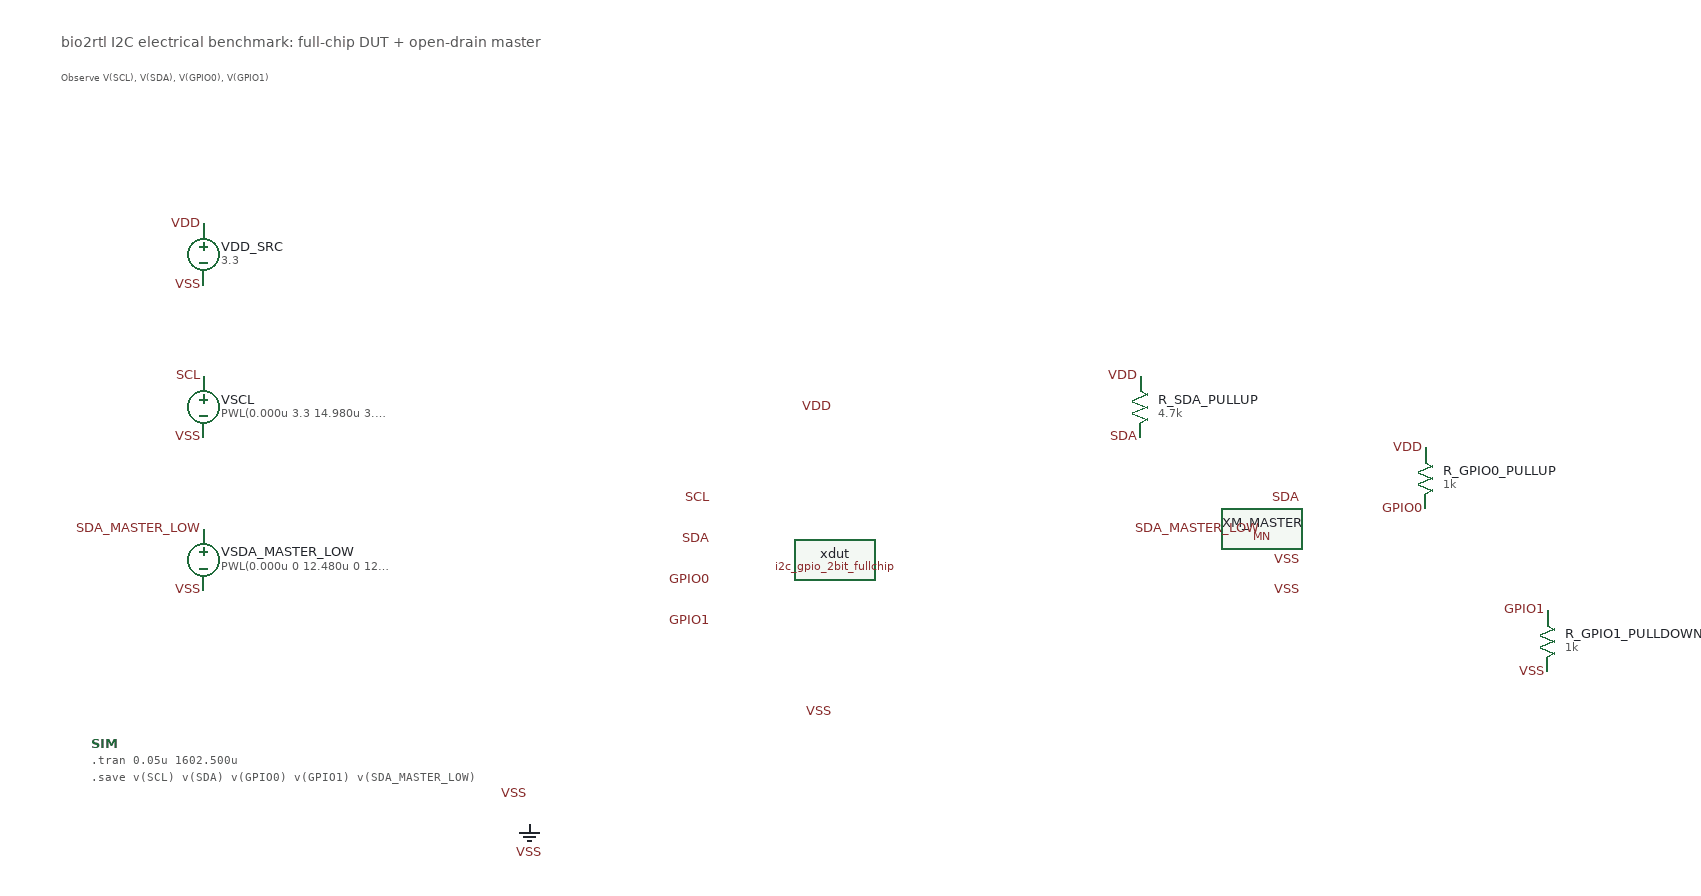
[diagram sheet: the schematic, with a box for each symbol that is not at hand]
v {xschem version=3.4.8RC file_version=1.3}
G {}
K {}
V {}
S {}
F {}
E {}
T {bio2rtl I2C electrical benchmark: full-chip DUT + open-drain master} -760 -520 0 0 0.42 0.42 {}
T {Observe V(SCL), V(SDA), V(GPIO0), V(GPIO1)} -760 -485 0 0 0.28 0.28 {}
C {i2c_gpio_2bit_fullchip.sym} 0 0 0 0 {name=xdut}
C {devices/lab_pin.sym} -120 -60 0 0 {name=d1 sig_type=std_logic lab=SCL}
C {devices/lab_pin.sym} -120 -20 0 0 {name=d2 sig_type=std_logic lab=SDA}
C {devices/lab_pin.sym} -120 20 0 0 {name=d3 sig_type=std_logic lab=GPIO0}
C {devices/lab_pin.sym} -120 60 0 0 {name=d4 sig_type=std_logic lab=GPIO1}
C {devices/lab_pin.sym} 0 -150 0 0 {name=d5 sig_type=std_logic lab=VDD}
C {devices/lab_pin.sym} 0 150 0 0 {name=d6 sig_type=std_logic lab=VSS}
C {devices/vsource.sym} -620 -300 0 0 {name=VDD_SRC value=3.3 savecurrent=false}
C {devices/lab_pin.sym} -620 -330 1 0 {name=vddp sig_type=std_logic lab=VDD}
C {devices/lab_pin.sym} -620 -270 1 0 {name=vddn sig_type=std_logic lab=VSS}
C {devices/vsource.sym} -620 -150 0 0 {name=VSCL value="PWL(0.000u 3.3 14.980u 3.3 15.000u 0 22.480u 0 22.500u 3.3 27.480u 3.3 27.500u 0 32.480u 0 32.500u 3.3 37.480u 3.3 37.500u 0 42.480u 0 42.500u 3.3 47.480u 3.3 47.500u 0 52.480u 0 52.500u 3.3 57.480u 3.3 57.500u 0 62.480u 0 62.500u 3.3 67.480u 3.3 67.500u 0 72.480u 0 72.500u 3.3 77.480u 3.3 77.500u 0 82.480u 0 82.500u 3.3 87.480u 3.3 87.500u 0 92.480u 0 92.500u 3.3 97.480u 3.3 97.500u 0 102.480u 0 102.500u 3.3 107.480u 3.3 107.500u 0 112.480u 0 112.500u 3.3 117.480u 3.3 117.500u 0 122.480u 0 122.500u 3.3 127.480u 3.3 127.500u 0 132.480u 0 132.500u 3.3 137.480u 3.3 137.500u 0 142.480u 0 142.500u 3.3 147.480u 3.3 147.500u 0 152.480u 0 152.500u 3.3 157.480u 3.3 157.500u 0 162.480u 0 162.500u 3.3 167.480u 3.3 167.500u 0 172.480u 0 172.500u 3.3 177.480u 3.3 177.500u 0 182.480u 0 182.500u 3.3 187.480u 3.3 187.500u 0 192.480u 0 192.500u 3.3 197.480u 3.3 197.500u 0 202.480u 0 202.500u 3.3 207.480u 3.3 207.500u 0 212.480u 0 212.500u 3.3 217.480u 3.3 217.500u 0 222.480u 0 222.500u 3.3 227.480u 3.3 227.500u 0 232.480u 0 232.500u 3.3 237.480u 3.3 237.500u 0 242.480u 0 242.500u 3.3 247.480u 3.3 247.500u 0 252.480u 0 252.500u 3.3 257.480u 3.3 257.500u 0 262.480u 0 262.500u 3.3 267.480u 3.3 267.500u 0 272.480u 0 272.500u 3.3 277.480u 3.3 277.500u 0 282.480u 0 282.500u 3.3 287.480u 3.3 287.500u 0 294.980u 0 295.000u 3.3 324.980u 3.3 325.000u 0 332.480u 0 332.500u 3.3 337.480u 3.3 337.500u 0 342.480u 0 342.500u 3.3 347.480u 3.3 347.500u 0 352.480u 0 352.500u 3.3 357.480u 3.3 357.500u 0 362.480u 0 362.500u 3.3 367.480u 3.3 367.500u 0 372.480u 0 372.500u 3.3 377.480u 3.3 377.500u 0 382.480u 0 382.500u 3.3 387.480u 3.3 387.500u 0 392.480u 0 392.500u 3.3 397.480u 3.3 397.500u 0 402.480u 0 402.500u 3.3 407.480u 3.3 407.500u 0 412.480u 0 412.500u 3.3 417.480u 3.3 417.500u 0 422.480u 0 422.500u 3.3 427.480u 3.3 427.500u 0 432.480u 0 432.500u 3.3 437.480u 3.3 437.500u 0 442.480u 0 442.500u 3.3 447.480u 3.3 447.500u 0 452.480u 0 452.500u 3.3 457.480u 3.3 457.500u 0 462.480u 0 462.500u 3.3 467.480u 3.3 467.500u 0 472.480u 0 472.500u 3.3 477.480u 3.3 477.500u 0 482.480u 0 482.500u 3.3 487.480u 3.3 487.500u 0 492.480u 0 492.500u 3.3 497.480u 3.3 497.500u 0 502.480u 0 502.500u 3.3 507.480u 3.3 507.500u 0 512.480u 0 512.500u 3.3 517.480u 3.3 517.500u 0 522.480u 0 522.500u 3.3 527.480u 3.3 527.500u 0 532.480u 0 532.500u 3.3 537.480u 3.3 537.500u 0 542.480u 0 542.500u 3.3 547.480u 3.3 547.500u 0 552.480u 0 552.500u 3.3 557.480u 3.3 557.500u 0 562.480u 0 562.500u 3.3 567.480u 3.3 567.500u 0 572.480u 0 572.500u 3.3 577.480u 3.3 577.500u 0 582.480u 0 582.500u 3.3 587.480u 3.3 587.500u 0 592.480u 0 592.500u 3.3 597.480u 3.3 597.500u 0 604.980u 0 605.000u 3.3 634.980u 3.3 635.000u 0 642.480u 0 642.500u 3.3 647.480u 3.3 647.500u 0 652.480u 0 652.500u 3.3 657.480u 3.3 657.500u 0 662.480u 0 662.500u 3.3 667.480u 3.3 667.500u 0 672.480u 0 672.500u 3.3 677.480u 3.3 677.500u 0 682.480u 0 682.500u 3.3 687.480u 3.3 687.500u 0 692.480u 0 692.500u 3.3 697.480u 3.3 697.500u 0 702.480u 0 702.500u 3.3 707.480u 3.3 707.500u 0 712.480u 0 712.500u 3.3 717.480u 3.3 717.500u 0 722.480u 0 722.500u 3.3 727.480u 3.3 727.500u 0 732.480u 0 732.500u 3.3 737.480u 3.3 737.500u 0 742.480u 0 742.500u 3.3 747.480u 3.3 747.500u 0 752.480u 0 752.500u 3.3 757.480u 3.3 757.500u 0 762.480u 0 762.500u 3.3 767.480u 3.3 767.500u 0 772.480u 0 772.500u 3.3 777.480u 3.3 777.500u 0 782.480u 0 782.500u 3.3 787.480u 3.3 787.500u 0 792.480u 0 792.500u 3.3 797.480u 3.3 797.500u 0 802.480u 0 802.500u 3.3 807.480u 3.3 807.500u 0 812.480u 0 812.500u 3.3 817.480u 3.3 817.500u 0 822.480u 0 822.500u 3.3 827.480u 3.3 827.500u 0 832.480u 0 832.500u 3.3 837.480u 3.3 837.500u 0 842.480u 0 842.500u 3.3 847.480u 3.3 847.500u 0 852.480u 0 852.500u 3.3 857.480u 3.3 857.500u 0 862.480u 0 862.500u 3.3 867.480u 3.3 867.500u 0 872.480u 0 872.500u 3.3 877.480u 3.3 877.500u 0 882.480u 0 882.500u 3.3 887.480u 3.3 887.500u 0 892.480u 0 892.500u 3.3 897.480u 3.3 897.500u 0 902.480u 0 902.500u 3.3 907.480u 3.3 907.500u 0 914.980u 0 915.000u 3.3 944.980u 3.3 945.000u 0 952.480u 0 952.500u 3.3 957.480u 3.3 957.500u 0 962.480u 0 962.500u 3.3 967.480u 3.3 967.500u 0 972.480u 0 972.500u 3.3 977.480u 3.3 977.500u 0 982.480u 0 982.500u 3.3 987.480u 3.3 987.500u 0 992.480u 0 992.500u 3.3 997.480u 3.3 997.500u 0 1002.480u 0 1002.500u 3.3 1007.480u 3.3 1007.500u 0 1012.480u 0 1012.500u 3.3 1017.480u 3.3 1017.500u 0 1022.480u 0 1022.500u 3.3 1027.480u 3.3 1027.500u 0 1032.480u 0 1032.500u 3.3 1037.480u 3.3 1037.500u 0 1042.480u 0 1042.500u 3.3 1047.480u 3.3 1047.500u 0 1052.480u 0 1052.500u 3.3 1057.480u 3.3 1057.500u 0 1062.480u 0 1062.500u 3.3 1067.480u 3.3 1067.500u 0 1072.480u 0 1072.500u 3.3 1077.480u 3.3 1077.500u 0 1082.480u 0 1082.500u 3.3 1087.480u 3.3 1087.500u 0 1092.480u 0 1092.500u 3.3 1097.480u 3.3 1097.500u 0 1102.480u 0 1102.500u 3.3 1107.480u 3.3 1107.500u 0 1112.480u 0 1112.500u 3.3 1117.480u 3.3 1117.500u 0 1122.480u 0 1122.500u 3.3 1127.480u 3.3 1127.500u 0 1129.980u 0 1130.000u 3.3 1137.480u 3.3 1137.500u 0 1144.980u 0 1145.000u 3.3 1149.980u 3.3 1150.000u 0 1154.980u 0 1155.000u 3.3 1159.980u 3.3 1160.000u 0 1164.980u 0 1165.000u 3.3 1169.980u 3.3 1170.000u 0 1174.980u 0 1175.000u 3.3 1179.980u 3.3 1180.000u 0 1184.980u 0 1185.000u 3.3 1189.980u 3.3 1190.000u 0 1194.980u 0 1195.000u 3.3 1199.980u 3.3 1200.000u 0 1204.980u 0 1205.000u 3.3 1209.980u 3.3 1210.000u 0 1214.980u 0 1215.000u 3.3 1219.980u 3.3 1220.000u 0 1224.980u 0 1225.000u 3.3 1229.980u 3.3 1230.000u 0 1234.980u 0 1235.000u 3.3 1239.980u 3.3 1240.000u 0 1244.980u 0 1245.000u 3.3 1249.980u 3.3 1250.000u 0 1254.980u 0 1255.000u 3.3 1259.980u 3.3 1260.000u 0 1264.980u 0 1265.000u 3.3 1269.980u 3.3 1270.000u 0 1274.980u 0 1275.000u 3.3 1279.980u 3.3 1280.000u 0 1284.980u 0 1285.000u 3.3 1289.980u 3.3 1290.000u 0 1294.980u 0 1295.000u 3.3 1299.980u 3.3 1300.000u 0 1304.980u 0 1305.000u 3.3 1309.980u 3.3 1310.000u 0 1314.980u 0 1315.000u 3.3 1319.980u 3.3 1320.000u 0 1324.980u 0 1325.000u 3.3 1329.980u 3.3 1330.000u 0 1334.980u 0 1335.000u 3.3 1339.980u 3.3 1340.000u 0 1344.980u 0 1345.000u 3.3 1349.980u 3.3 1350.000u 0 1354.980u 0 1355.000u 3.3 1359.980u 3.3 1360.000u 0 1364.980u 0 1365.000u 3.3 1369.980u 3.3 1370.000u 0 1374.980u 0 1375.000u 3.3 1379.980u 3.3 1380.000u 0 1384.980u 0 1385.000u 3.3 1389.980u 3.3 1390.000u 0 1394.980u 0 1395.000u 3.3 1399.980u 3.3 1400.000u 0 1404.980u 0 1405.000u 3.3 1409.980u 3.3 1410.000u 0 1417.480u 0 1417.500u 3.3 1447.480u 3.3 1447.500u 0 1454.980u 0 1455.000u 3.3 1459.980u 3.3 1460.000u 0 1464.980u 0 1465.000u 3.3 1469.980u 3.3 1470.000u 0 1474.980u 0 1475.000u 3.3 1479.980u 3.3 1480.000u 0 1484.980u 0 1485.000u 3.3 1489.980u 3.3 1490.000u 0 1494.980u 0 1495.000u 3.3 1499.980u 3.3 1500.000u 0 1504.980u 0 1505.000u 3.3 1509.980u 3.3 1510.000u 0 1514.980u 0 1515.000u 3.3 1519.980u 3.3 1520.000u 0 1524.980u 0 1525.000u 3.3 1529.980u 3.3 1530.000u 0 1534.980u 0 1535.000u 3.3 1539.980u 3.3 1540.000u 0 1547.480u 0 1547.500u 3.3)" savecurrent=false}
C {devices/lab_pin.sym} -620 -180 1 0 {name=sclp sig_type=std_logic lab=SCL}
C {devices/lab_pin.sym} -620 -120 1 0 {name=scln sig_type=std_logic lab=VSS}
C {devices/vsource.sym} -620 0 0 0 {name=VSDA_MASTER_LOW value="PWL(0.000u 0 12.480u 0 12.500u 3.3 19.980u 3.3 20.000u 0 29.980u 0 30.000u 3.3 69.980u 3.3 70.000u 0 79.980u 0 80.000u 3.3 99.980u 3.3 100.000u 0 109.980u 0 110.000u 3.3 189.980u 3.3 190.000u 0 199.980u 0 200.000u 3.3 279.980u 3.3 280.000u 0 289.980u 0 290.000u 3.3 299.980u 3.3 300.000u 0 322.480u 0 322.500u 3.3 329.980u 3.3 330.000u 0 339.980u 0 340.000u 3.3 379.980u 3.3 380.000u 0 389.980u 0 390.000u 3.3 409.980u 3.3 410.000u 0 419.980u 0 420.000u 3.3 489.980u 3.3 490.000u 0 509.980u 0 510.000u 3.3 579.980u 3.3 580.000u 0 599.980u 0 600.000u 3.3 609.980u 3.3 610.000u 0 632.480u 0 632.500u 3.3 639.980u 3.3 640.000u 0 649.980u 0 650.000u 3.3 689.980u 3.3 690.000u 0 699.980u 0 700.000u 3.3 719.980u 3.3 720.000u 0 729.980u 0 730.000u 3.3 809.980u 3.3 810.000u 0 819.980u 0 820.000u 3.3 879.980u 3.3 880.000u 0 909.980u 0 910.000u 3.3 919.980u 3.3 920.000u 0 942.480u 0 942.500u 3.3 949.980u 3.3 950.000u 0 959.980u 0 960.000u 3.3 999.980u 3.3 1000.000u 0 1009.980u 0 1010.000u 3.3 1029.980u 3.3 1030.000u 0 1039.980u 0 1040.000u 3.3 1099.980u 3.3 1100.000u 0 1109.980u 0 1110.000u 3.3 1119.980u 3.3 1120.000u 0 1134.980u 0 1135.000u 3.3 1142.480u 3.3 1142.500u 0 1152.480u 0 1152.500u 3.3 1192.480u 3.3 1192.500u 0 1202.480u 0 1202.500u 3.3 1212.480u 3.3 1212.500u 0 1312.480u 0 1312.500u 3.3 1322.480u 3.3 1322.500u 0 1412.480u 0 1412.500u 3.3 1422.480u 3.3 1422.500u 0 1444.980u 0 1445.000u 3.3 1452.480u 3.3 1452.500u 0 1462.480u 0 1462.500u 3.3 1502.480u 3.3 1502.500u 0 1522.480u 0 1522.500u 3.3 1532.480u 3.3 1532.500u 0 1542.480u 0 1542.500u 3.3 1552.480u 3.3 1552.500u 0)" savecurrent=false}
C {devices/lab_pin.sym} -620 -30 1 0 {name=sgp sig_type=std_logic lab=SDA_MASTER_LOW}
C {devices/lab_pin.sym} -620 30 1 0 {name=sgn sig_type=std_logic lab=VSS}
C {devices/res.sym} 300 -150 0 0 {name=R_SDA_PULLUP value=4.7k footprint=1206 device=resistor m=1}
C {devices/lab_pin.sym} 300 -180 1 0 {name=rp1 sig_type=std_logic lab=VDD}
C {devices/lab_pin.sym} 300 -120 1 0 {name=rp2 sig_type=std_logic lab=SDA}
C {TR-1umLIB/MN.sym} 420 -30 0 0 {name=XM_MASTER model=NMOS w=30u l=1u m=9 spiceprefix=X as=0 ad=0 ps=0 pd=0 nrd=0 nrs=0}
C {devices/lab_pin.sym} 460 -60 1 0 {name=md sig_type=std_logic lab=SDA}
C {devices/lab_pin.sym} 420 -30 0 0 {name=mg sig_type=std_logic lab=SDA_MASTER_LOW}
C {devices/lab_pin.sym} 460 0 1 0 {name=mb sig_type=std_logic lab=VSS}
C {devices/lab_pin.sym} 460 30 1 0 {name=ms sig_type=std_logic lab=VSS}
C {devices/res.sym} 580 -80 0 0 {name=R_GPIO0_PULLUP value=1k footprint=1206 device=resistor m=1}
C {devices/lab_pin.sym} 580 -110 1 0 {name=g0a sig_type=std_logic lab=VDD}
C {devices/lab_pin.sym} 580 -50 1 0 {name=g0b sig_type=std_logic lab=GPIO0}
C {devices/res.sym} 700 80 0 0 {name=R_GPIO1_PULLDOWN value=1k footprint=1206 device=resistor m=1}
C {devices/lab_pin.sym} 700 50 1 0 {name=g1a sig_type=std_logic lab=GPIO1}
C {devices/lab_pin.sym} 700 110 1 0 {name=g1b sig_type=std_logic lab=VSS}
C {devices/gnd.sym} -300 260 0 0 {name=GND1 lab=VSS}
C {devices/lab_pin.sym} -300 230 1 0 {name=gndvss sig_type=std_logic lab=VSS}
C {devices/code_shown.sym} -730 180 0 0 {name=SIM only_toplevel=false value=".tran 0.05u 1602.500u
.save v(SCL) v(SDA) v(GPIO0) v(GPIO1) v(SDA_MASTER_LOW)"}
